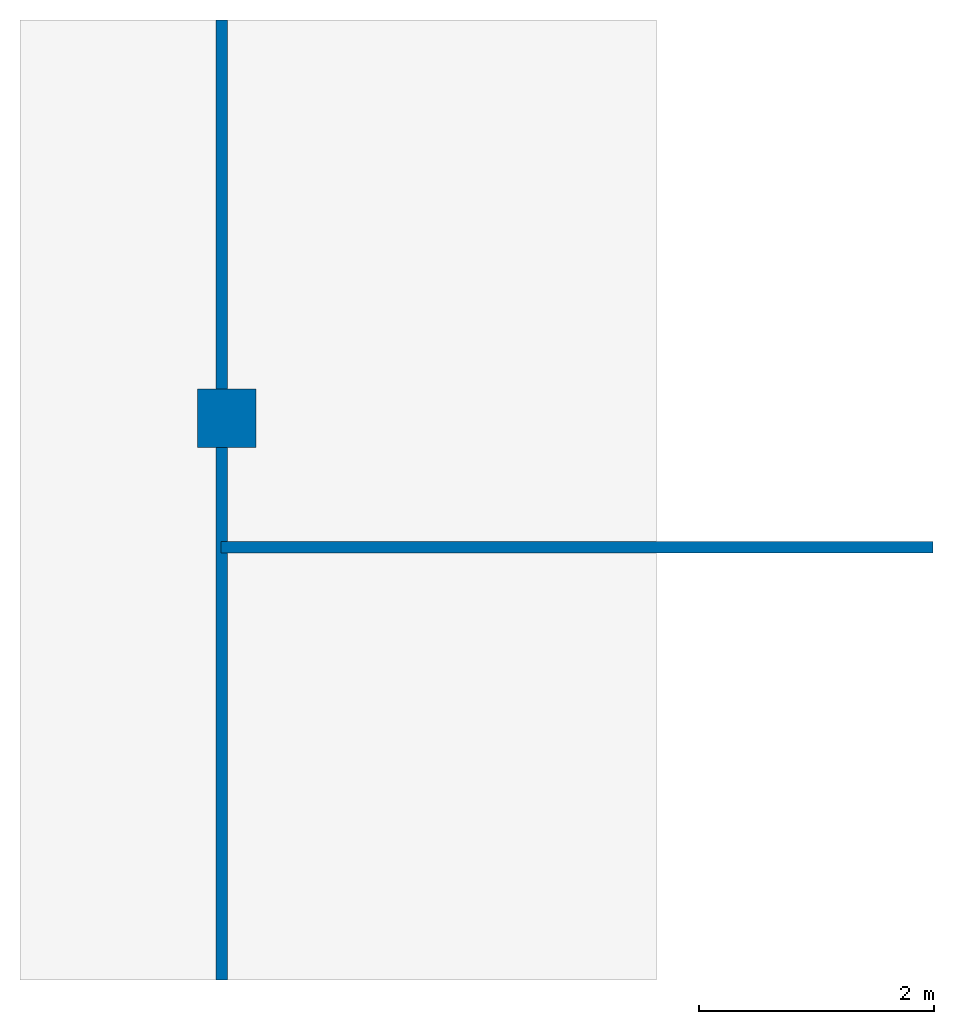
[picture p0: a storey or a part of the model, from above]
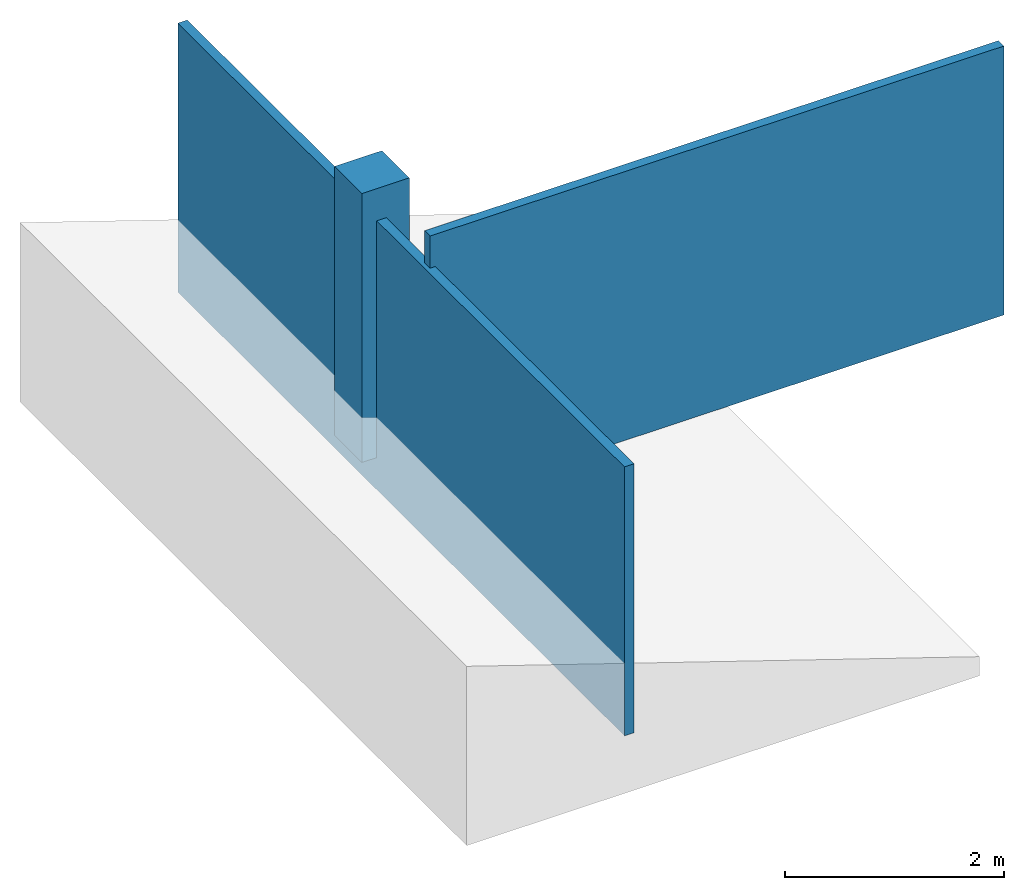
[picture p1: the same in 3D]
Properties of the parts of a building model (IFC4)

# File
Description: ViewDefinition[DesignTransferView]
File name: Untitled.ifc
Time: 2025-09-17T17:07:48+08:00
Written by: IfcOpenShell 0.8.4-alpha250910
Made in: Bonsai 0.8.4-alpha250910-36da945
Authorization: Nobody

# IfcProject, My Project
Document: SOUTH ELEVATION; NORTH SECTION; MY STOREY PLAN

# IfcAnnotation: DRAWING (3)
EPset_Drawing - HasUnderlay: no; HasLinework: yes; HasAnnotation: yes; GlobalReferencing: yes; Stylesheet: drawings/assets/default.css; Markers: drawings/assets/markers.svg; Symbols: drawings/assets/symbols.svg; Patterns: drawings/assets/patterns.svg; ShadingStyles: drawings/assets/shading_styles.json; CurrentShadingStyle: Blender Default
Name | Document | TargetView | Scale | HumanScale | Group
SOUTH ELEVATION | X drawings/SOUTH ELEVATION.svg | ELEVATION_VIEW | 1/100 | 1:100 | SOUTH ELEVATION
NORTH SECTION | X drawings/NORTH SECTION.svg | SECTION_VIEW | 1/10 | 1:10 | NORTH SECTION
MY STOREY PLAN | X drawings/MY STOREY PLAN.svg | PLAN_VIEW | 1/10 | 1:10 | MY STOREY PLAN

# IfcAnnotation: ELEVATION, IfcAnnotation/SOUTH ELEVATION
Group: MY STOREY PLAN

# IfcAnnotation: SECTION, IfcAnnotation/NORTH SECTION
Group: MY STOREY PLAN

# IfcAnnotation: SECTION_LEVEL, IfcBuildingStorey/My Storey
Group: NORTH SECTION

# IfcColumn: dd, Column
In: My Storey
Type - PredefinedType: COLUMN; Material: concrete
EPset_Parametric - Engine: Bonsai.DumbProfile

# IfcGeographicElement, Cube
In: My Storey
PredefinedType: TERRAIN; Material: earth 100 mm

# IfcWall: Unnamed, Wall
In: My Storey
Type - PredefinedType: SOLIDWALL; Material: brick 100 mm
Type - EPset_Parametric - LayerSetDirection: AXIS2
EPset_Parametric - Engine: Bonsai.DumbLayer2

# IfcWall: dd, Wall
In: My Storey
Type - PredefinedType: MOVABLE; Material: concrete 100 mm
Type - EPset_Parametric - LayerSetDirection: AXIS2
EPset_Parametric - Engine: Bonsai.DumbLayer2
